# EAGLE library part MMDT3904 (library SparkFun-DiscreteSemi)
Dual NPN transistor

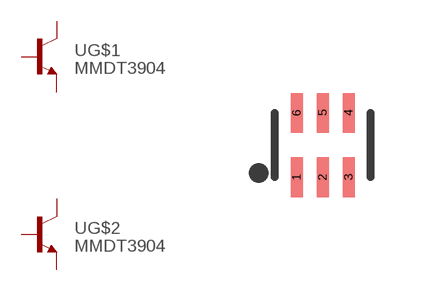
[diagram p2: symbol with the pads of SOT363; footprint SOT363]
Designator prefix -; gates G$1=NPN G$2=NPN

## MMDT3904  [SOT363]
1  G$2:E  pas
2  G$2:B  pas
3  G$1:C  pas
4  G$1:E  pas
5  G$1:B  pas
6  G$2:C  pas

## Footprint SOT363 (pad centres in mm)
smd 0.3 x 0.99: 1 -0.65,-0.8; 2 0,-0.8; 3 0.65,-0.8; 4 0.65,0.81; 5 0,0.81; 6 -0.65,0.81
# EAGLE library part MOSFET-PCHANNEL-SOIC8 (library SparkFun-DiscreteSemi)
Generic 8-pin PMOSFET

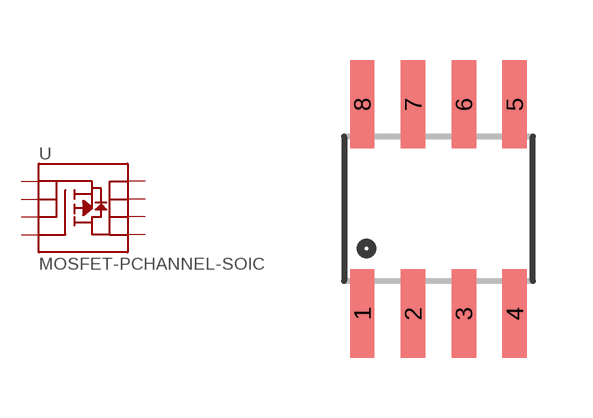
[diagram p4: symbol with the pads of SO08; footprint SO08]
Designator prefix -

## MOSFET-PCHANNEL-SOIC8SOIC8  [SO08]
1  S
2  S
3  S
4  G
5  D
6  D
7  D
8  D

## Footprint SO08 (pad centres in mm)
Small Outline Package Fits JEDEC packages (narrow SOIC-8)
smd 0.61 x 2.21: 1 -1.905,-2.616; 2 -0.635,-2.616; 3 0.635,-2.616; 4 1.905,-2.616; 5 1.905,2.616; 6 0.635,2.616; 7 -0.635,2.616; 8 -1.905,2.616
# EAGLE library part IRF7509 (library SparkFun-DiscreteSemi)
30V Dual PMOS/NMOS MSOP-8 NMOS RDS .11-ohm PMOS RDS .20-ohm TRANS-07913

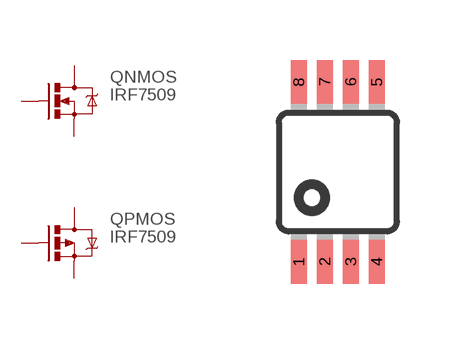
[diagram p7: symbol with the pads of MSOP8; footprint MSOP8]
Designator prefix Q; gates NMOS=MOSFET-NCHANNEL PMOS=MOSFET-PCHANNEL

## IRF7509 (PROD_ID: TRANS-07913)  [MSOP8]
1  NMOS:S  pas
2  NMOS:G  pas
3  PMOS:S  pas
4  PMOS:G  pas
5  PMOS:D  pas
6  PMOS:D  pas
7  NMOS:D  pas
8  NMOS:D  pas

## Footprint MSOP8 (pad centres in mm)
8M, 8-Lead, 0.118" Wide, Miniature Small Outline Package MSOP 8M-Package doc1097.pdf
smd 0.4 x 1.1: 1 -0.975,-2.25; 2 -0.325,-2.25; 3 0.325,-2.25; 4 0.975,-2.25; 5 0.975,2.25; 6 0.325,2.25; 7 -0.325,2.25; 8 -0.975,2.25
